# Reusable pad-cell LEF only; the complete frame remains a GDS overlay.
# Fixed top-level pins are in libs.ref/ICPS2023_5_fd_base_2x2/def/ICPS2023_5_fd_base_2x2.def.
# Layer names follow libs.tech/klayout/doc/layers.md.
# A process LEF tech file is not shipped.
VERSION 5.7 ;
BUSBITCHARS "[]" ;
DIVIDERCHAR "/" ;
UNITS
  DATABASE MICRONS 1000 ;   # PDK database unit is 0.001 um
END UNITS
MANUFACTURINGGRID 0.001 ;

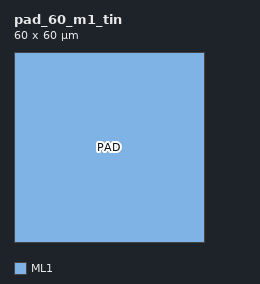
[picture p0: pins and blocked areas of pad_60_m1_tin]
MACRO pad_60_m1_tin
  CLASS PAD ;
  ORIGIN 0 0 ;
  FOREIGN pad_60_m1_tin 0 0 ;
  SIZE 60.0 BY 60.0 ;
  SYMMETRY X Y ;
  PIN PAD
    DIRECTION INOUT ;
    USE ANALOG ;
    PORT
      LAYER ML1 ;
      RECT 0.0 0.0 60.0 60.0 ;
    END
  END PAD
  OBS
    LAYER CNT ;
      RECT 5.0 4.0 10.0 9.0 ;
      RECT 20.0 4.0 25.0 9.0 ;
      RECT 35.0 4.0 40.0 9.0 ;
      RECT 50.0 4.0 55.0 9.0 ;
      RECT 5.0 19.0 10.0 24.0 ;
      RECT 20.0 19.0 25.0 24.0 ;
      RECT 35.0 19.0 40.0 24.0 ;
      RECT 50.0 19.0 55.0 24.0 ;
      RECT 5.0 34.0 10.0 39.0 ;
      RECT 20.0 34.0 25.0 39.0 ;
      RECT 35.0 34.0 40.0 39.0 ;
      RECT 50.0 34.0 55.0 39.0 ;
      RECT 5.0 49.0 10.0 54.0 ;
      RECT 20.0 49.0 25.0 54.0 ;
      RECT 35.0 49.0 40.0 54.0 ;
      RECT 50.0 49.0 55.0 54.0 ;
    LAYER TIN ;
      RECT 0.0 0.0 60.0 60.0 ;
  END
END pad_60_m1_tin
